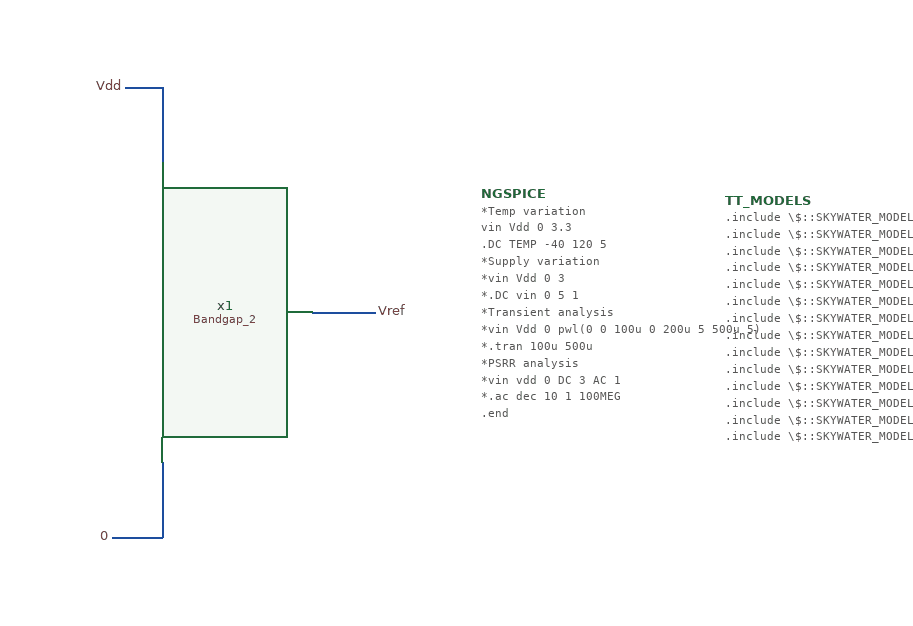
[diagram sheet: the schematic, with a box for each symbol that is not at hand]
v {xschem version=2.9.9 file_version=1.2 }
G {}
K {}
V {}
S {}
E {}
N 2630 -1100 2660 -1100 { lab=Vdd}
N 2780 -920 2830 -920 { lab=Vref}
N 2660 -1100 2660 -1040 { lab=Vdd}
N 2620 -740 2660 -740 { lab=0}
N 2660 -800 2660 -740 { lab=0}
C {devices/code_shown.sym} 2915 -1015 0 0 {name=NGSPICE
only_toplevel=true
value="
*Temp variation
vin Vdd 0 3.3
.DC TEMP -40 120 5
*Supply variation
*vin Vdd 0 3
*.DC vin 0 5 1
*Transient analysis
*vin Vdd 0 pwl(0 0 100u 0 200u 5 500u 5)
*.tran 100u 500u
*PSRR analysis
*vin vdd 0 DC 3 AC 1  
*.ac dec 10 1 100MEG
.end
" }
C {devices/code.sym} 3110 -1010 0 0 {name=TT_MODELS
spice_ignore=false
only_toplevel=true
format="tcleval( @value )"
value="
.include \\\\$::SKYWATER_MODELS\\\\/cells/nfet_01v8/sky130_fd_pr__nfet_01v8__tt.corner.spice
.include \\\\$::SKYWATER_MODELS\\\\/cells/nfet_01v8_lvt/sky130_fd_pr__nfet_01v8_lvt__tt.corner.spice
.include \\\\$::SKYWATER_MODELS\\\\/cells/pfet_01v8/sky130_fd_pr__pfet_01v8__tt.corner.spice
.include \\\\$::SKYWATER_MODELS\\\\/cells/nfet_03v3_nvt/sky130_fd_pr__nfet_03v3_nvt__tt.corner.spice
.include \\\\$::SKYWATER_MODELS\\\\/cells/nfet_05v0_nvt/sky130_fd_pr__nfet_05v0_nvt__tt.corner.spice
.include \\\\$::SKYWATER_MODELS\\\\/cells/esd_nfet_01v8/sky130_fd_pr__esd_nfet_01v8__tt.corner.spice
.include \\\\$::SKYWATER_MODELS\\\\/cells/pfet_01v8_lvt/sky130_fd_pr__pfet_01v8_lvt__tt.corner.spice
.include \\\\$::SKYWATER_MODELS\\\\/cells/pfet_01v8_hvt/sky130_fd_pr__pfet_01v8_hvt__tt.corner.spice
.include \\\\$::SKYWATER_MODELS\\\\/cells/esd_pfet_g5v0d10v5/sky130_fd_pr__esd_pfet_g5v0d10v5__tt.corner.spice
.include \\\\$::SKYWATER_MODELS\\\\/cells/pfet_g5v0d10v5/sky130_fd_pr__pfet_g5v0d10v5__tt.corner.spice
.include \\\\$::SKYWATER_MODELS\\\\/cells/pfet_g5v0d16v0/sky130_fd_pr__pfet_g5v0d16v0__tt.corner.spice
.include \\\\$::SKYWATER_MODELS\\\\/cells/nfet_g5v0d10v5/sky130_fd_pr__nfet_g5v0d10v5__tt.corner.spice
.include \\\\$::SKYWATER_MODELS\\\\/cells/nfet_g5v0d16v0/sky130_fd_pr__nfet_g5v0d16v0__tt_discrete.corner.spice
.include \\\\$::SKYWATER_MODELS\\\\/cells/esd_nfet_g5v0d10v5/sky130_fd_pr__esd_nfet_g5v0d10v5__tt.corner.spice
.include \\\\$::SKYWATER_MODELS\\\\/models/corners/tt/nonfet.spice
* Mismatch parameters
.include \\\\$::SKYWATER_MODELS\\\\/cells/nfet_01v8/sky130_fd_pr__nfet_01v8__mismatch.corner.spice
.include \\\\$::SKYWATER_MODELS\\\\/cells/pfet_01v8/sky130_fd_pr__pfet_01v8__mismatch.corner.spice
.include \\\\$::SKYWATER_MODELS\\\\/cells/nfet_01v8_lvt/sky130_fd_pr__nfet_01v8_lvt__mismatch.corner.spice
.include \\\\$::SKYWATER_MODELS\\\\/cells/pfet_01v8_lvt/sky130_fd_pr__pfet_01v8_lvt__mismatch.corner.spice
.include \\\\$::SKYWATER_MODELS\\\\/cells/pfet_01v8_hvt/sky130_fd_pr__pfet_01v8_hvt__mismatch.corner.spice
.include \\\\$::SKYWATER_MODELS\\\\/cells/nfet_g5v0d10v5/sky130_fd_pr__nfet_g5v0d10v5__mismatch.corner.spice
.include \\\\$::SKYWATER_MODELS\\\\/cells/pfet_g5v0d10v5/sky130_fd_pr__pfet_g5v0d10v5__mismatch.corner.spice
.include \\\\$::SKYWATER_MODELS\\\\/cells/nfet_05v0_nvt/sky130_fd_pr__nfet_05v0_nvt__mismatch.corner.spice
.include \\\\$::SKYWATER_MODELS\\\\/cells/nfet_03v3_nvt/sky130_fd_pr__nfet_03v3_nvt__mismatch.corner.spice
* Resistor\\\\$::SKYWATER_MODELS\\\\/Capacitor
.include \\\\$::SKYWATER_MODELS\\\\/models/r+c/res_typical__cap_typical.spice
.include \\\\$::SKYWATER_MODELS\\\\/models/r+c/res_typical__cap_typical__lin.spice
* Special cells
.include \\\\$::SKYWATER_MODELS\\\\/models/corners/tt/specialized_cells.spice
* All models
.include \\\\$::SKYWATER_MODELS\\\\/models/all.spice
* Corner
.include \\\\$::SKYWATER_MODELS\\\\/models/corners/tt/rf.spice
"}
C {devices/lab_pin.sym} 2630 -1100 0 0 {name=l1 sig_type=std_logic lab=Vdd}
C {devices/lab_pin.sym} 2620 -740 0 0 {name=l2 sig_type=std_logic lab=0}
C {devices/lab_pin.sym} 2830 -920 0 1 {name=l3 sig_type=std_logic lab=Vref}
C {/home/eslam/Analog_blocks/Analog_Blocks/Bandgap/Schematics/BGR_2/Bandgap_2.sym} 2660 -920 0 0 {name=x1}
